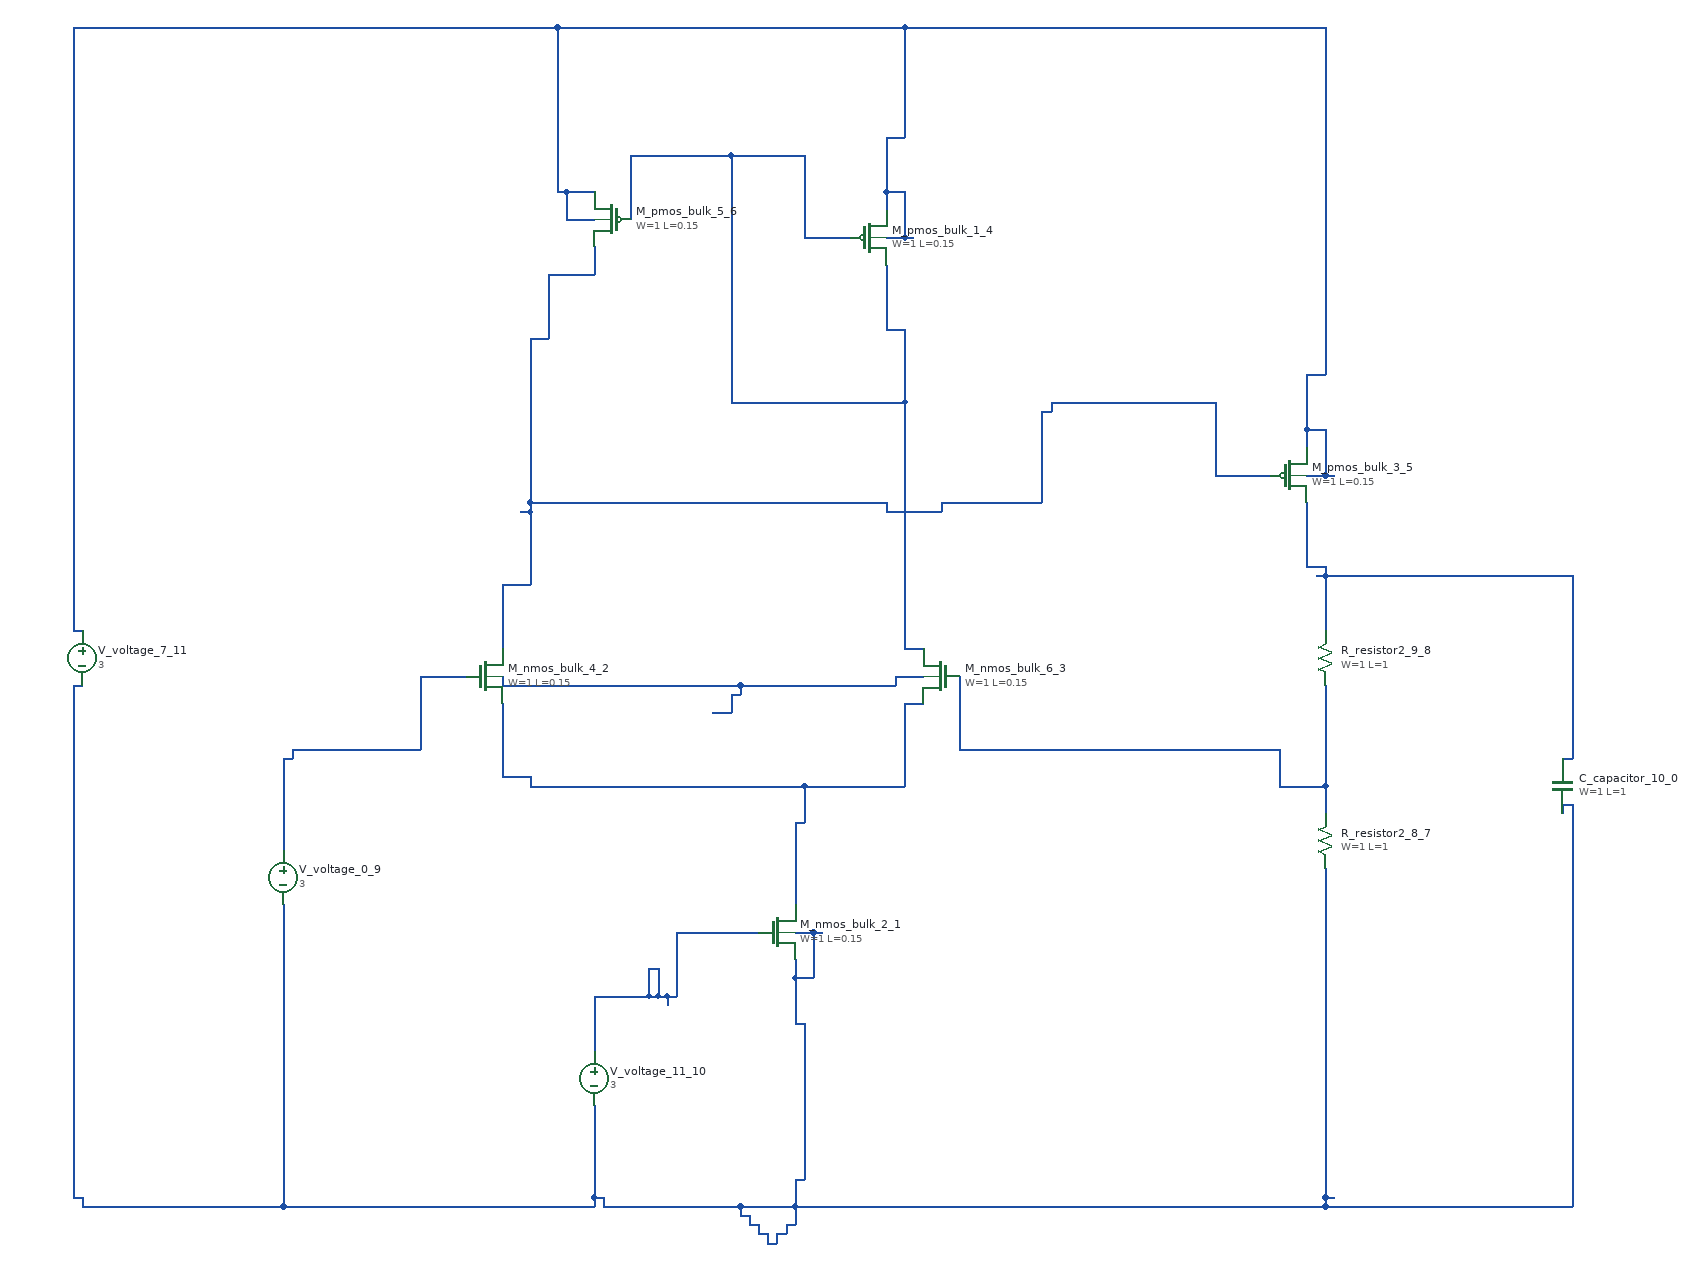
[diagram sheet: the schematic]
v {xschem version=3.4.8 file_version=1.2}
G {}
K {}
V {}
S {}
E {}
C {sky130_fd_pr/cap_mim_m3_1.sym} 1780 920 2 0 {name="C_capacitor_10_0" model=cap_mim_m3_1 W=1 L=1 MF=1 spiceprefix=X}
C {sky130_fd_pr/nfet_01v8.sym} 920 1080 0 0 {name="M_nmos_bulk_2_1"
W=1
L=0.15
nf=1 
mult=1
ad="expr('int((@nf + 1)/2) * @W / @nf * 0.29')"
pd="expr('2*int((@nf + 1)/2) * (@W / @nf + 0.29)')"
as="expr('int((@nf + 2)/2) * @W / @nf * 0.29')"
ps="expr('2*int((@nf + 2)/2) * (@W / @nf + 0.29)')"
nrd="expr('0.29 / @W ')" nrs="expr('0.29 / @W ')"
sa=0 sb=0 sd=0
model=nfet_01v8
spiceprefix=X
}
C {sky130_fd_pr/nfet_01v8.sym} 600 800 0 0 {name="M_nmos_bulk_4_2"
W=1
L=0.15
nf=1 
mult=1
ad="expr('int((@nf + 1)/2) * @W / @nf * 0.29')"
pd="expr('2*int((@nf + 1)/2) * (@W / @nf + 0.29)')"
as="expr('int((@nf + 2)/2) * @W / @nf * 0.29')"
ps="expr('2*int((@nf + 2)/2) * (@W / @nf + 0.29)')"
nrd="expr('0.29 / @W ')" nrs="expr('0.29 / @W ')"
sa=0 sb=0 sd=0
model=nfet_01v8
spiceprefix=X
}
C {sky130_fd_pr/nfet_01v8.sym} 1100 800 0 1 {name="M_nmos_bulk_6_3"
W=1
L=0.15
nf=1 
mult=1
ad="expr('int((@nf + 1)/2) * @W / @nf * 0.29')"
pd="expr('2*int((@nf + 1)/2) * (@W / @nf + 0.29)')"
as="expr('int((@nf + 2)/2) * @W / @nf * 0.29')"
ps="expr('2*int((@nf + 2)/2) * (@W / @nf + 0.29)')"
nrd="expr('0.29 / @W ')" nrs="expr('0.29 / @W ')"
sa=0 sb=0 sd=0
model=nfet_01v8
spiceprefix=X
}
C {sky130_fd_pr/pfet_01v8.sym} 1020 320 0 0 {name="M_pmos_bulk_1_4"
W=1
L=0.15
nf=1
mult=1
ad="expr('int((@nf + 1)/2) * @W / @nf * 0.29')"
pd="expr('2*int((@nf + 1)/2) * (@W / @nf + 0.29)')"
as="expr('int((@nf + 2)/2) * @W / @nf * 0.29')"
ps="expr('2*int((@nf + 2)/2) * (@W / @nf + 0.29)')"
nrd="expr('0.29 / @W ')" nrs="expr('0.29 / @W ')"
sa=0 sb=0 sd=0
model=pfet_01v8
spiceprefix=X
}
C {sky130_fd_pr/pfet_01v8.sym} 1480 580 0 0 {name="M_pmos_bulk_3_5"
W=1
L=0.15
nf=1
mult=1
ad="expr('int((@nf + 1)/2) * @W / @nf * 0.29')"
pd="expr('2*int((@nf + 1)/2) * (@W / @nf + 0.29)')"
as="expr('int((@nf + 2)/2) * @W / @nf * 0.29')"
ps="expr('2*int((@nf + 2)/2) * (@W / @nf + 0.29)')"
nrd="expr('0.29 / @W ')" nrs="expr('0.29 / @W ')"
sa=0 sb=0 sd=0
model=pfet_01v8
spiceprefix=X
}
C {sky130_fd_pr/pfet_01v8.sym} 740 300 0 1 {name="M_pmos_bulk_5_6"
W=1
L=0.15
nf=1
mult=1
ad="expr('int((@nf + 1)/2) * @W / @nf * 0.29')"
pd="expr('2*int((@nf + 1)/2) * (@W / @nf + 0.29)')"
as="expr('int((@nf + 2)/2) * @W / @nf * 0.29')"
ps="expr('2*int((@nf + 2)/2) * (@W / @nf + 0.29)')"
nrd="expr('0.29 / @W ')" nrs="expr('0.29 / @W ')"
sa=0 sb=0 sd=0
model=pfet_01v8
spiceprefix=X
}
C {sky130_fd_pr/res_generic_po.sym} 1520 980 2 0 {name="R_resistor2_8_7"
W=1
L=1
model=res_generic_po
spiceprefix=X
mult=1}
C {sky130_fd_pr/res_generic_po.sym} 1520 780 2 0 {name="R_resistor2_9_8"
W=1
L=1
model=res_generic_po
spiceprefix=X
mult=1}
C {devices/vsource.sym} 380 1020 0 0 {name="V_voltage_0_9" value=3 savecurrent=false}
C {devices/vsource.sym} 720 1240 0 0 {name="V_voltage_11_10" value=3 savecurrent=false}
C {devices/vsource.sym} 160 780 0 0 {name="V_voltage_7_11" value=3 savecurrent=false}
N 1780 890 1790 890 {}
N 1510 690 1520 690 {}
N 1520 690 1790 690 {}
N 1500 680 1520 680 {}
N 1500 680 1500 610 {}
N 1520 750 1520 690 {}
N 1520 690 1520 680 {}
N 1790 890 1790 690 {}
N 910 1420 920 1420 {}
N 900 1410 910 1410 {}
N 920 1410 930 1410 {}
N 890 1400 900 1400 {}
N 930 1400 940 1400 {}
N 880 1390 890 1390 {}
N 160 1380 380 1380 {}
N 380 1380 720 1380 {}
N 730 1380 880 1380 {}
N 880 1380 940 1380 {}
N 940 1380 1520 1380 {}
N 1520 1380 1790 1380 {}
N 150 1370 160 1370 {}
N 720 1370 730 1370 {}
N 1520 1370 1530 1370 {}
N 940 1350 950 1350 {}
N 940 1180 950 1180 {}
N 940 1130 960 1130 {}
N 940 1080 960 1080 {}
N 960 1080 970 1080 {}
N 1780 940 1790 940 {}
N 150 810 160 810 {}
N 150 1370 150 810 {}
N 160 1380 160 1370 {}
N 380 1380 380 1050 {}
N 720 1380 720 1370 {}
N 720 1370 720 1270 {}
N 730 1380 730 1370 {}
N 880 1390 880 1380 {}
N 890 1400 890 1390 {}
N 900 1410 900 1400 {}
N 910 1420 910 1410 {}
N 920 1420 920 1410 {}
N 930 1410 930 1400 {}
N 940 1400 940 1380 {}
N 940 1380 940 1350 {}
N 940 1180 940 1130 {}
N 940 1130 940 1110 {}
N 950 1350 950 1180 {}
N 960 1130 960 1080 {}
N 1520 1380 1520 1370 {}
N 1520 1370 1520 1010 {}
N 1780 950 1780 940 {}
N 1790 1380 1790 940 {}
N 850 840 870 840 {}
N 870 820 880 820 {}
N 620 810 880 810 {}
N 880 810 1050 810 {}
N 1050 800 1080 800 {}
N 620 810 620 800 {}
N 870 840 870 820 {}
N 880 820 880 810 {}
N 1050 810 1050 800 {}
N 940 960 950 960 {}
N 650 920 950 920 {}
N 950 920 1060 920 {}
N 620 910 650 910 {}
N 1060 830 1080 830 {}
N 620 910 620 830 {}
N 650 920 650 910 {}
N 940 1050 940 960 {}
N 950 960 950 920 {}
N 1060 920 1060 830 {}
N 1060 770 1080 770 {}
N 870 500 1060 500 {}
N 1040 420 1060 420 {}
N 950 320 1000 320 {}
N 760 230 870 230 {}
N 870 230 950 230 {}
N 760 300 760 230 {}
N 870 500 870 230 {}
N 950 320 950 230 {}
N 1040 420 1040 350 {}
N 1060 770 1060 500 {}
N 1060 500 1060 420 {}
N 150 750 160 750 {}
N 1500 580 1520 580 {}
N 1520 580 1530 580 {}
N 1500 530 1520 530 {}
N 1500 470 1520 470 {}
N 1040 320 1060 320 {}
N 1060 320 1070 320 {}
N 690 300 720 300 {}
N 680 270 690 270 {}
N 690 270 720 270 {}
N 1040 270 1060 270 {}
N 1040 210 1060 210 {}
N 150 90 680 90 {}
N 680 90 1060 90 {}
N 1060 90 1520 90 {}
N 150 750 150 90 {}
N 680 270 680 90 {}
N 690 300 690 270 {}
N 1040 290 1040 270 {}
N 1040 270 1040 210 {}
N 1060 320 1060 270 {}
N 1060 210 1060 90 {}
N 1500 550 1500 530 {}
N 1500 530 1500 470 {}
N 1520 580 1520 530 {}
N 1520 470 1520 90 {}
N 620 700 650 700 {}
N 640 620 650 620 {}
N 1040 620 1100 620 {}
N 650 610 1040 610 {}
N 1100 610 1210 610 {}
N 1400 580 1460 580 {}
N 1210 510 1220 510 {}
N 1220 500 1400 500 {}
N 650 430 670 430 {}
N 670 360 720 360 {}
N 620 770 620 700 {}
N 650 700 650 620 {}
N 650 620 650 610 {}
N 650 610 650 430 {}
N 670 430 670 360 {}
N 720 360 720 330 {}
N 1040 620 1040 610 {}
N 1100 620 1100 610 {}
N 1210 610 1210 510 {}
N 1220 510 1220 500 {}
N 1400 580 1400 500 {}
N 1470 920 1520 920 {}
N 1120 880 1470 880 {}
N 1120 880 1120 800 {}
N 1470 920 1470 880 {}
N 1520 950 1520 920 {}
N 1520 920 1520 810 {}
N 380 890 390 890 {}
N 390 880 530 880 {}
N 530 800 580 800 {}
N 380 990 380 890 {}
N 390 890 390 880 {}
N 530 880 530 800 {}
N 720 1150 780 1150 {}
N 780 1150 790 1150 {}
N 790 1150 800 1150 {}
N 800 1150 810 1150 {}
N 780 1120 790 1120 {}
N 810 1080 900 1080 {}
N 720 1210 720 1150 {}
N 780 1150 780 1120 {}
N 790 1150 790 1120 {}
N 800 1160 800 1150 {}
N 810 1150 810 1080 {}
